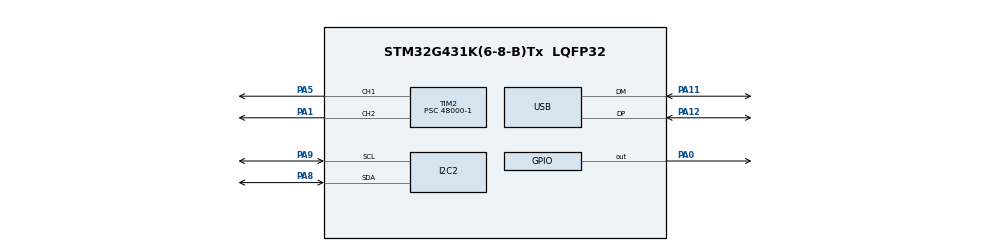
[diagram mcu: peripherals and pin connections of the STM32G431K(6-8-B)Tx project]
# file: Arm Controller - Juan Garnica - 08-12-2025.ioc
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I2C2.OwnAddress=50
I2C2.Timing=0x20B17DB6
Mcu.Family=STM32G4
Mcu.Name=STM32G431K(6-8-B)Tx
Mcu.Package=LQFP32
NVIC.I2C2_ER_IRQn=true\:0\:0\:false\:false\:true\:true\:true\:true
NVIC.I2C2_EV_IRQn=true\:0\:0\:false\:false\:true\:true\:true\:true
NVIC.PriorityGroup=NVIC_PRIORITYGROUP_4
NVIC.USB_LP_IRQn=true\:0\:0\:false\:false\:true\:false\:true\:true
PA0.Signal=GPIO_Output
PA1.Signal=S_TIM2_CH2
PA11.Mode=Device
PA11.Signal=USB_DM
PA12.Mode=Device
PA12.Signal=USB_DP
PA13.Mode=Trace_Asynchronous_SW
PA13.Signal=SYS_JTMS-SWDIO
PA14.Mode=Trace_Asynchronous_SW
PA14.Signal=SYS_JTCK-SWCLK
PA5.Signal=S_TIM2_CH1
PA8.Mode=I2C
PA8.Signal=I2C2_SDA
PA9.Mode=I2C
PA9.Signal=I2C2_SCL
PB3.Mode=Trace_Asynchronous_SW
PB3.Signal=SYS_JTDO-SWO
PF0-OSC_IN.Mode=HSE-External-Oscillator
PF0-OSC_IN.Signal=RCC_OSC_IN
PF1-OSC_OUT.Mode=HSE-External-Oscillator
PF1-OSC_OUT.Signal=RCC_OSC_OUT
ProjectManager.HeapSize=0x200
ProjectManager.StackSize=0x400
ProjectManager.TargetToolchain=STM32CubeIDE
RCC.ADC12Freq_Value=96000000
RCC.AHBFreq_Value=96000000
RCC.APB1Freq_Value=96000000
RCC.APB1TimFreq_Value=96000000
RCC.APB2Freq_Value=96000000
RCC.APB2TimFreq_Value=96000000
RCC.CortexFreq_Value=96000000
RCC.EXTERNAL_CLOCK_VALUE=12288000
RCC.HCLKFreq_Value=96000000
RCC.HSE_VALUE=16000000
RCC.HSI48_VALUE=48000000
RCC.HSI_VALUE=16000000
RCC.LSE_VALUE=32768
RCC.PLLN=12
RCC.PLLQ=RCC_PLLQ_DIV4
RCC.PLLSourceVirtual=RCC_PLLSOURCE_HSE
RCC.SYSCLKFreq_VALUE=96000000
RCC.SYSCLKSource=RCC_SYSCLKSOURCE_PLLCLK
RCC.USBFreq_Value=48000000
RCC.VCOOutputFreq_Value=192000000
SH.S_TIM2_CH1.0=TIM2_CH1,PWM Generation1 CH1
SH.S_TIM2_CH2.0=TIM2_CH2,PWM Generation2 CH2
TIM2.Channel-PWM\ Generation1\ CH1=TIM_CHANNEL_1
TIM2.Channel-PWM\ Generation2\ CH2=TIM_CHANNEL_2
TIM2.Prescaler=48000-1
USB_DEVICE.CLASS_NAME_FS=DFU
USB_DEVICE.VirtualMode=Dfu
USB_DEVICE.VirtualModeFS=Dfu_FS
VP_SYS_VS_DBSignals.Mode=DisableDeadBatterySignals
VP_TIM2_VS_ClockSourceINT.Mode=Internal
VP_USB_DEVICE_VS_USB_DEVICE_DFU_FS.Mode=DFU_FS
board=custom

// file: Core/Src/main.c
/* USER CODE BEGIN Header */
/**
 ******************************************************************************
 * @file           : main.c
 * @brief          : Main program body
 ******************************************************************************
 * @attention
 * Copyright (c) 2025 STMicroelectronics.
 * All rights reserved.
 * This software is licensed under terms that can be found in the LICENSE file
 * in the root directory of this software component.
 * If no LICENSE file comes with this software, it is provided AS-IS.
 ******************************************************************************
 */
/* USER CODE END Header */
#include "main.h"
#include "usb_device.h"
#include "i2c_slave.h"

/* USER CODE BEGIN PD */

// Typical safe range for many servos; widen only if confirmed
#define SERVO_MIN_US 1000
#define SERVO_MAX_US 2000

/* USER CODE END PD */

/* USER CODE BEGIN PM */
static inline uint16_t clamp_u16(int v, int lo, int hi) {
  return (uint16_t)((v < lo) ? lo : (v > hi ? hi : v));
}
/* USER CODE END PM */

I2C_HandleTypeDef hi2c2;
TIM_HandleTypeDef htim2;

void SystemClock_Config(void);
static void MX_GPIO_Init(void);
static void MX_TIM2_Init(void);
static void MX_I2C2_Init(void);
/* USER CODE BEGIN PFP */

// 0–180° → microseconds
static inline uint16_t angle_to_us(uint8_t deg) {
  if (deg > 180) deg = 180;
  return (uint16_t)(SERVO_MIN_US + ((uint32_t)(SERVO_MAX_US - SERVO_MIN_US) * deg) / 180U);
}

// Set TIM2 CH1 pulse width in microseconds (CCR == µs)
static inline void servo_write_us(uint16_t us) {
  __HAL_TIM_SET_COMPARE(&htim2, TIM_CHANNEL_1, clamp_u16(us, SERVO_MIN_US, SERVO_MAX_US));
}

// Convenience
static inline void servo_write_deg(uint8_t deg) { servo_write_us(angle_to_us(deg)); }

/* USER CODE END PFP */

int main(void)
{
  HAL_Init();
  SystemClock_Config();

  MX_GPIO_Init();
  MX_TIM2_Init();
  MX_I2C2_Init();
  MX_USB_Device_Init();

  /* USER CODE BEGIN 2 */
  // Start PWM at 1 MHz base (1 µs/tick), 20 ms period
  HAL_TIM_PWM_Start(&htim2, TIM_CHANNEL_1);
  servo_write_deg(90);  // center on boot

  if (HAL_I2C_EnableListen_IT(&hi2c2) != HAL_OK) {
    Error_Handler();
  }
  /* USER CODE END 2 */

  while (1)
  {
    process_i2c_cmd();   // handle I2C writes → servo updates
    // HAL_Delay(1);     // optional small sleep

    HAL_Delay(500);
    servo_write_deg(45);  // center on boot

    HAL_Delay(500);
    servo_write_deg(135);  // center on boot

  }
}

void SystemClock_Config(void)
{
  RCC_OscInitTypeDef RCC_OscInitStruct = {0};
  RCC_ClkInitTypeDef RCC_ClkInitStruct = {0};

  HAL_PWREx_ControlVoltageScaling(PWR_REGULATOR_VOLTAGE_SCALE1);

  RCC_OscInitStruct.OscillatorType = RCC_OSCILLATORTYPE_HSI48|RCC_OSCILLATORTYPE_HSE;
  RCC_OscInitStruct.HSEState  = RCC_HSE_ON;
  RCC_OscInitStruct.HSI48State= RCC_HSI48_ON;
  RCC_OscInitStruct.PLL.PLLState = RCC_PLL_ON;
  RCC_OscInitStruct.PLL.PLLSource= RCC_PLLSOURCE_HSE;
  RCC_OscInitStruct.PLL.PLLM    = RCC_PLLM_DIV2;
  RCC_OscInitStruct.PLL.PLLN    = 12;
  RCC_OscInitStruct.PLL.PLLP    = RCC_PLLP_DIV2;
  RCC_OscInitStruct.PLL.PLLQ    = RCC_PLLQ_DIV4;
  RCC_OscInitStruct.PLL.PLLR    = RCC_PLLR_DIV2;
  if (HAL_RCC_OscConfig(&RCC_OscInitStruct) != HAL_OK) { Error_Handler(); }

  RCC_ClkInitStruct.ClockType      = RCC_CLOCKTYPE_HCLK|RCC_CLOCKTYPE_SYSCLK
                                   |RCC_CLOCKTYPE_PCLK1|RCC_CLOCKTYPE_PCLK2;
  RCC_ClkInitStruct.SYSCLKSource   = RCC_SYSCLKSOURCE_PLLCLK;
  RCC_ClkInitStruct.AHBCLKDivider  = RCC_SYSCLK_DIV1;
  RCC_ClkInitStruct.APB1CLKDivider = RCC_HCLK_DIV1;
  RCC_ClkInitStruct.APB2CLKDivider = RCC_HCLK_DIV1;

  if (HAL_RCC_ClockConfig(&RCC_ClkInitStruct, FLASH_LATENCY_1) != HAL_OK) { Error_Handler(); }
}

static void MX_TIM2_Init(void)
{
  TIM_ClockConfigTypeDef sClockSourceConfig = {0};
  TIM_MasterConfigTypeDef sMasterConfig     = {0};
  TIM_OC_InitTypeDef sConfigOC              = {0};

  htim2.Instance               = TIM2;

  // *** Servo-friendly base: 1 MHz (1 µs/tick), 20 ms period ***
  htim2.Init.Prescaler         = 48 - 1;     // 48 MHz / 48 = 1 MHz
  htim2.Init.CounterMode       = TIM_COUNTERMODE_UP;
  htim2.Init.Period            = 20000 - 1;  // 20,000 µs frame (50 Hz)
  htim2.Init.ClockDivision     = TIM_CLOCKDIVISION_DIV1;
  htim2.Init.AutoReloadPreload = TIM_AUTORELOAD_PRELOAD_DISABLE;

  if (HAL_TIM_Base_Init(&htim2) != HAL_OK) { Error_Handler(); }
  sClockSourceConfig.ClockSource = TIM_CLOCKSOURCE_INTERNAL;
  if (HAL_TIM_ConfigClockSource(&htim2, &sClockSourceConfig) != HAL_OK) { Error_Handler(); }
  if (HAL_TIM_PWM_Init(&htim2) != HAL_OK) { Error_Handler(); }

  sMasterConfig.MasterOutputTrigger = TIM_TRGO_RESET;
  sMasterConfig.MasterSlaveMode     = TIM_MASTERSLAVEMODE_DISABLE;
  if (HAL_TIMEx_MasterConfigSynchronization(&htim2, &sMasterConfig) != HAL_OK) { Error_Handler(); }

  sConfigOC.OCMode       = TIM_OCMODE_PWM1;
  sConfigOC.Pulse        = 0;
  sConfigOC.OCPolarity   = TIM_OCPOLARITY_HIGH;
  sConfigOC.OCFastMode   = TIM_OCFAST_DISABLE;

  if (HAL_TIM_PWM_ConfigChannel(&htim2, &sConfigOC, TIM_CHANNEL_1) != HAL_OK) { Error_Handler(); }
  if (HAL_TIM_PWM_ConfigChannel(&htim2, &sConfigOC, TIM_CHANNEL_2) != HAL_OK) { Error_Handler(); }

  HAL_TIM_MspPostInit(&htim2);
}

static void MX_I2C2_Init(void)
{
  hi2c2.Instance = I2C2;
  hi2c2.Init.Timing           = 0x10805D88;
  hi2c2.Init.OwnAddress1      = (0x4F << 1);
  hi2c2.Init.AddressingMode   = I2C_ADDRESSINGMODE_7BIT;
  hi2c2.Init.DualAddressMode  = I2C_DUALADDRESS_DISABLE;
  hi2c2.Init.OwnAddress2      = 0;
  hi2c2.Init.OwnAddress2Masks = I2C_OA2_NOMASK;
  hi2c2.Init.GeneralCallMode  = I2C_GENERALCALL_DISABLE;
  hi2c2.Init.NoStretchMode    = I2C_NOSTRETCH_DISABLE;
  if (HAL_I2C_Init(&hi2c2) != HAL_OK) { Error_Handler(); }
  if (HAL_I2CEx_ConfigAnalogFilter(&hi2c2, I2C_ANALOGFILTER_ENABLE) != HAL_OK) { Error_Handler(); }
  if (HAL_I2CEx_ConfigDigitalFilter(&hi2c2, 0) != HAL_OK) { Error_Handler(); }
}

static void MX_GPIO_Init(void)
{
  GPIO_InitTypeDef GPIO_InitStruct = {0};

  __HAL_RCC_GPIOF_CLK_ENABLE();
  __HAL_RCC_GPIOA_CLK_ENABLE();
  __HAL_RCC_GPIOB_CLK_ENABLE();

  HAL_GPIO_WritePin(GPIOA, GPIO_PIN_0, GPIO_PIN_RESET);

  GPIO_InitStruct.Pin   = GPIO_PIN_0;
  GPIO_InitStruct.Mode  = GPIO_MODE_OUTPUT_PP;
  GPIO_InitStruct.Pull  = GPIO_NOPULL;
  GPIO_InitStruct.Speed = GPIO_SPEED_FREQ_LOW;
  HAL_GPIO_Init(GPIOA, &GPIO_InitStruct);
}

void Error_Handler(void)
{
  __disable_irq();
  while (1) {}
}
